VERSION 5.8 ;
BUSBITCHARS "[]" ;
DIVIDERCHAR "/" ;
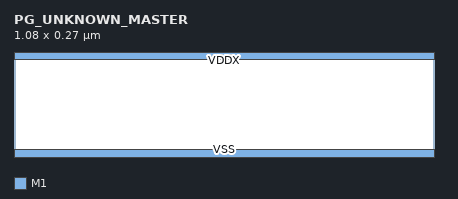
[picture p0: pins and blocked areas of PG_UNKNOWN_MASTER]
MACRO PG_UNKNOWN_MASTER
 CLASS CORE ;
 ORIGIN 0 0 ;
 SIZE 1.08 BY 0.27 ;
 SYMMETRY X Y ;
 SITE asap7sc7p5t ;
 PIN VDDX
  DIRECTION INOUT ; USE POWER ;
  PORT
   LAYER M1 ; RECT 0 0.25 1.08 0.27 ;
  END
 END VDDX
 PIN VSS
  DIRECTION INOUT ; USE GROUND ;
  PORT
   LAYER M1 ; RECT 0 0 1.08 0.02 ;
  END
 END VSS
END PG_UNKNOWN_MASTER
END LIBRARY
